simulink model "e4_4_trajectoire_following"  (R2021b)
settings: Solver=FixedStepAuto  StartTime=0.0  StopTime=200  FixedStep=sampleTime  RelTol=1e-3  EnableMultiTasking=on
InitFcn:
  | start;
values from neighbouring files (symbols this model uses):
  k_d_x = 1.65    [start.m]    (also in startSimulation.m = 2)
  k_d_y = 1.52    [start.m]    (also in startSimulation.m = 2.65)
  k_d_yaw = 1    [start.m]    (also in startSimulation.m = 1.6)
  k_d_z = 0.5    [start.m]    (also in startSimulation.m = 1)
  k_i_x = 0.9    [start.m]    (also in startSimulation.m = 0.001)
  k_i_y = 0.91    [start.m]    (also in startSimulation.m = 0.01)
  k_i_yaw = 0.01    [start.m]    (also in startSimulation.m)
  k_i_z = 0.01    [start.m]    (also in startSimulation.m = 0)
  k_p_x = 1.9    [start.m]    (also in startSimulation.m = 1.55)
  k_p_y = 1.9    [start.m]    (also in startSimulation.m = 2.5)
  k_p_yaw = 2    [start.m]    (also in startSimulation.m = 10)
  k_p_z = 2    [start.m]    (also in startSimulation.m = 10)
  sampleTime = 0.01    [start.m]    (also in startSimulation.m)
  saturation_psi = 2    [start.m]    (also in startSimulation.m)
  saturation_x = 2    [start.m]    (also in startSimulation.m)
  saturation_y = 2    [start.m]    (also in startSimulation.m)
  saturation_z = 2    [start.m]    (also in startSimulation.m)
libraries: simulink x2, aerolibanimutils x1

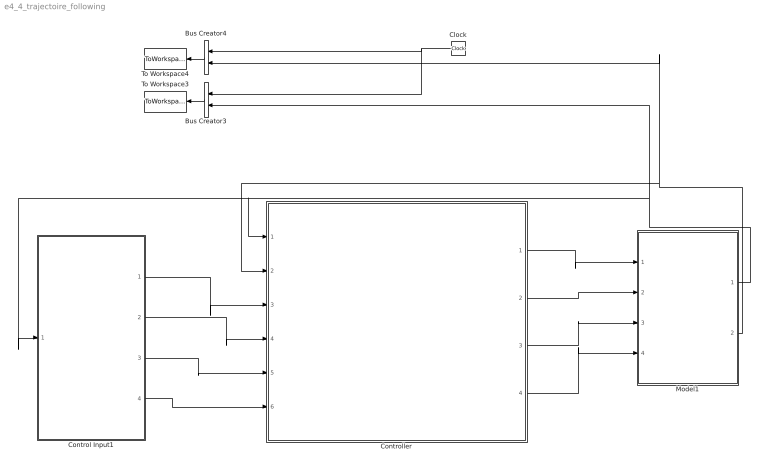
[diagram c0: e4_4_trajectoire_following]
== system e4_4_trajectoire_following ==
  Bus Creator3 : BusCreator  Inputs=2
  Bus Creator4 : BusCreator  Inputs=2
  Clock : Clock
  Control Input1 : Subsystem
  Controller : Subsystem
  Model1 : Subsystem
  To Workspace3 : ToWorkspace  VariableName=r1_pos_array1  SampleTime=-1
  To Workspace4 : ToWorkspace  VariableName=r1_vel_array1  SampleTime=-1
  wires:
  Controller/2(Controller Output Y) -> Model1/2(uy)
  Controller/3(Controller Output H) -> Model1/3(uz)
  Controller/4(Controller Output Psi) -> Model1/4(upsi)
  Model1/2(Output Velocity1) -> Bus Creator4/2, Controller/2(Feedback Velocity)
  Model1/1(Output Postion1) -> Bus Creator3/2, Control Input1/1(Position Feedback), Controller/1(Feedback Position)
  Bus Creator3/1 -> To Workspace3/1
  Clock/1 -> Bus Creator3/1, Bus Creator4/1
  Bus Creator4/1 -> To Workspace4/1
  Control Input1/2(uy) -> Controller/4(Control input Y)
  Control Input1/1(ux) -> Controller/3(Control input X)
  Control Input1/3(uz) -> Controller/5(Control input H)
  Control Input1/4(upsi) -> Controller/6(Control input Psi)
  Controller/1(Controller Output X) -> Model1/1(ux)

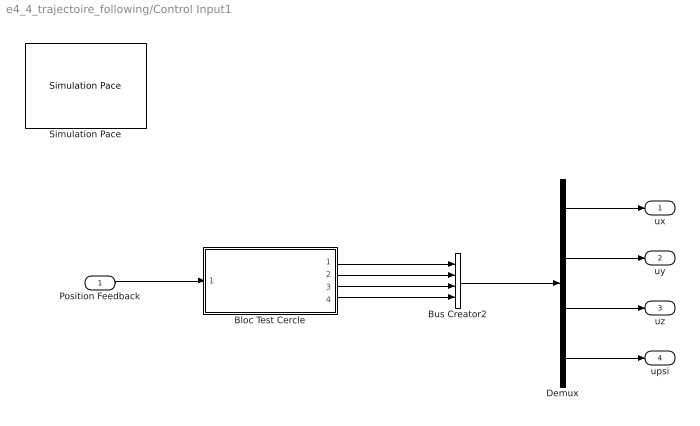
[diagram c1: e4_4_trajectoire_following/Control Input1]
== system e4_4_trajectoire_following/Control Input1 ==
  Position Feedback : Inport
  Bloc Test Cercle : Subsystem
  Bus Creator2 : BusCreator  Inputs=4
  Demux : Demux
  Simulation Pace : aerolibanimutils/Simulation Pace  SimulationPace=100  SleepMode=MATLAB Thread  OutputPaceError=off  SampleTime=-1
  ux : Outport  VectorParamsAs1DForOutWhenUnconnected=off
  uy : Outport  Port=2  VectorParamsAs1DForOutWhenUnconnected=off
  uz : Outport  Port=3  VectorParamsAs1DForOutWhenUnconnected=off
  upsi : Outport  Port=4  VectorParamsAs1DForOutWhenUnconnected=off
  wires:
  Demux/2 -> uy/1
  Demux/1 -> ux/1
  Demux/3 -> uz/1
  Demux/4 -> upsi/1
  Bloc Test Cercle/2(uy) -> Bus Creator2/2
  Bloc Test Cercle/4(upsi) -> Bus Creator2/4
  Position Feedback/1 -> Bloc Test Cercle/1(Position Feedback)
  Bloc Test Cercle/3(uz) -> Bus Creator2/3
  Bus Creator2/1 -> Demux/1
  Bloc Test Cercle/1(ux) -> Bus Creator2/1

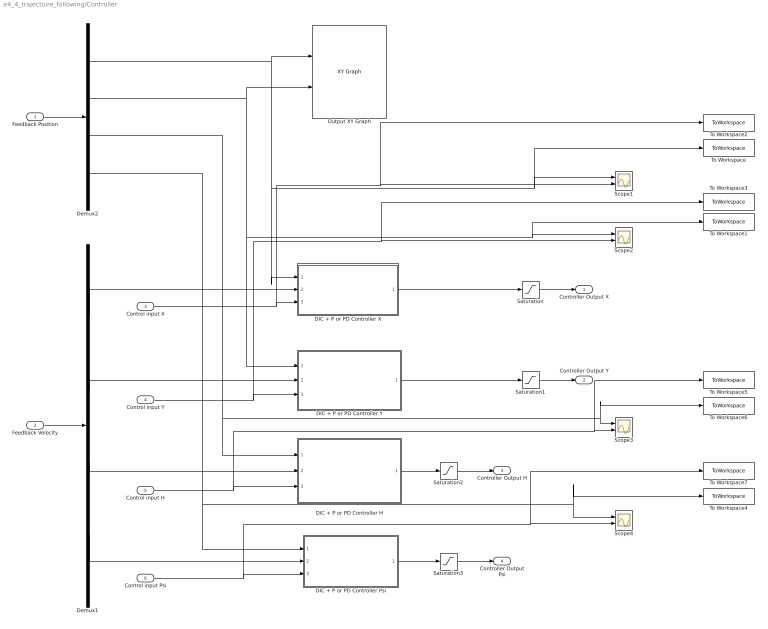
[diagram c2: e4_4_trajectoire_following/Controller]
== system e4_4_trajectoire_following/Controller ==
  Feedback Position : Inport
  Feedback Velocity : Inport  Port=2
  Control input X : Inport  Port=3
  Control input Y : Inport  Port=4
  Control input H : Inport  Port=5
  Control input Psi : Inport  Port=6
  DIC + P or PD Controller H : Subsystem
  DIC + P or PD Controller Psi : Subsystem
  DIC + P or PD Controller X : Subsystem
  DIC + P or PD Controller Y : Subsystem
  Demux1 : Demux
  Demux2 : Demux
  Output XY Graph : simulink/Sinks/XY Graph  xmin=-1  xmax=1  ymin=-1  ymax=1  st=-1
  Saturation : Saturate  UpperLimit=saturation_x  LowerLimit=-saturation_x
  Saturation1 : Saturate  UpperLimit=saturation_y  LowerLimit=-saturation_y
  Saturation2 : Saturate  UpperLimit=saturation_z  LowerLimit=-saturation_z
  Saturation3 : Saturate  UpperLimit=saturation_psi  LowerLimit=-saturation_psi
  Scope{1..4} (4 alike) : Scope  NumInputPorts=2
  To Workspace : ToWorkspace  VariableName=N4_Step1_Out_X  SampleTime=-1
  To Workspace1 : ToWorkspace  VariableName=N4_Step1_Out_Y  SampleTime=-1
  To Workspace2 : ToWorkspace  VariableName=N4_Step1_In_X  SampleTime=-1
  To Workspace3 : ToWorkspace  VariableName=N4_Step1_In_Y  SampleTime=-1
  To Workspace4 : ToWorkspace  VariableName=N4_Step1_Out_Psi  SampleTime=-1
  To Workspace5 : ToWorkspace  VariableName=N4_Step1_In_H  SampleTime=-1
  To Workspace6 : ToWorkspace  VariableName=N4_Step1_Out_H  SampleTime=-1
  To Workspace7 : ToWorkspace  VariableName=N4_Step1_In_Psi  SampleTime=-1
  Controller Output X : Outport  VectorParamsAs1DForOutWhenUnconnected=off
  Controller Output Y : Outport  Port=2  VectorParamsAs1DForOutWhenUnconnected=off
  Controller Output H : Outport  Port=3  VectorParamsAs1DForOutWhenUnconnected=off
  Controller Output Psi : Outport  Port=4  VectorParamsAs1DForOutWhenUnconnected=off
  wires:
  Feedback Position/1 -> Demux2/1
  Feedback Velocity/1 -> Demux1/1
  Demux1/2 -> DIC + P or PD Controller Y/2(Feedback Velocity Y)
  Demux2/3 -> Scope3/1, To Workspace6/1, DIC + P or PD Controller H/1(Feedback Position H)
  Demux1/1 -> DIC + P or PD Controller X/2(Feedback Velocity X)
  Demux1/3 -> DIC + P or PD Controller H/2(Feedback Velocity H)
  Control input X/1 -> To Workspace2/1, Scope1/2, DIC + P or PD Controller X/3(Control Input X)
  Control input H/1 -> Scope3/2, To Workspace5/1, DIC + P or PD Controller H/3(Control Input H)
  Saturation/1 -> Controller Output X/1
  Saturation1/1 -> Controller Output Y/1
  Saturation2/1 -> Controller Output H/1
  Saturation3/1 -> Controller Output Psi/1
  Control input Y/1 -> Scope2/2, To Workspace3/1, DIC + P or PD Controller Y/3(Control Input Y)
  DIC + P or PD Controller H/1(Controller Output H) -> Saturation2/1
  DIC + P or PD Controller Psi/1(Controller Output Psi) -> Saturation3/1
  Demux2/1 -> DIC + P or PD Controller X/1(Feedback Position X), To Workspace/1, Scope1/1, Output XY Graph/1
  Demux2/2 -> Scope2/1, To Workspace1/1, DIC + P or PD Controller Y/1(Feedback Position Y), Output XY Graph/2
  Demux2/4 -> Scope4/1, To Workspace4/1, DIC + P or PD Controller Psi/1(Feedback Position Psi)
  Demux1/4 -> DIC + P or PD Controller Psi/2(Feedback Velocity Psi)
  Control input Psi/1 -> Scope4/2, To Workspace7/1, DIC + P or PD Controller Psi/3(Control input Psi)
  DIC + P or PD Controller Y/1(Controller Output Y) -> Saturation1/1
  DIC + P or PD Controller X/1(Controller Output X) -> Saturation/1

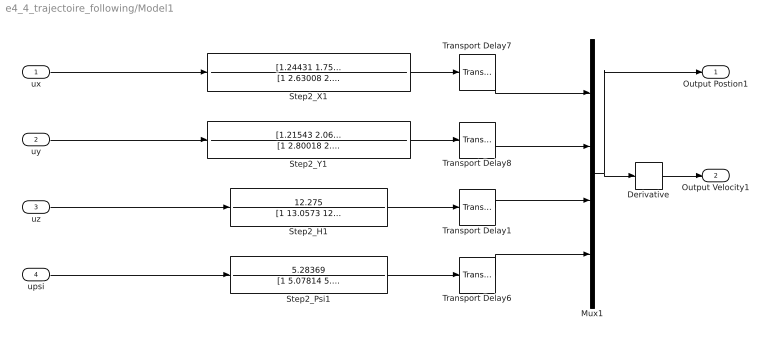
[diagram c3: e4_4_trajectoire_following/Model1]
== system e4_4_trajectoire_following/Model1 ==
  ux : Inport
  uy : Inport  Port=2
  uz : Inport  Port=3
  upsi : Inport  Port=4
  Derivative : Derivative
  Mux1 : Mux
  Step2_H1 : TransferFcn  Numerator=12.275  Denominator=[1 13.0573 12.3932]
  Step2_Psi1 : TransferFcn  Numerator=5.28369  Denominator=[1 5.07814 5.37552]
  Step2_X1 : TransferFcn  Numerator=[1.24431 1.75269]  Denominator=[1 2.63008 2.37405 1.95897]
  Step2_Y1 : TransferFcn  Numerator=[1.21543 2.06629]  Denominator=[1 2.80018 2.54762 2.23605]
  Transport Delay1 : TransportDelay  DelayTime=0.0271
  Transport Delay6 : TransportDelay  DelayTime=0.0281
  Transport Delay7 : TransportDelay  DelayTime=0.3778
  Transport Delay8 : TransportDelay  DelayTime=0.3715
  Output Postion1 : Outport
  Output Velocity1 : Outport  Port=2
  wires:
  upsi/1 -> Step2_Psi1/1
  Transport Delay8/1 -> Mux1/2
  Step2_Y1/1 -> Transport Delay8/1
  Step2_Psi1/1 -> Transport Delay6/1
  Transport Delay6/1 -> Mux1/4
  Transport Delay1/1 -> Mux1/3
  ux/1 -> Step2_X1/1
  Step2_X1/1 -> Transport Delay7/1
  Transport Delay7/1 -> Mux1/1
  Step2_H1/1 -> Transport Delay1/1
  uz/1 -> Step2_H1/1
  uy/1 -> Step2_Y1/1
  Derivative/1 -> Output Velocity1/1
  Mux1/1 -> Derivative/1, Output Postion1/1

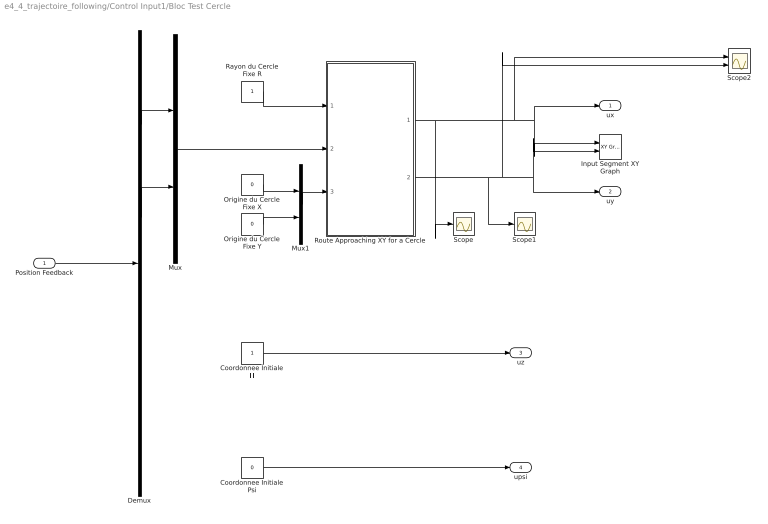
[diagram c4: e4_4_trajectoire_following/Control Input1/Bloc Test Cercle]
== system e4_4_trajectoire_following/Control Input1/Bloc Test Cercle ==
  Position Feedback : Inport
  Coordonnee Initiale H : Constant
  Coordonnee Initiale Psi : Constant  Value=0
  Demux : Demux
  Input Segment XY Graph : simulink/Sinks/XY Graph  xmin=-10  xmax=10  ymin=-10  ymax=10  st=-1
  Mux : Mux  Inputs=2
  Mux1 : Mux  Inputs=2
  Origine du Cercle Fixe X : Constant  Value=0
  Origine du Cercle Fixe Y : Constant  Value=0
  Rayon du Cercle Fixe R : Constant
  Route Approaching XY for a Cercle : MATLAB Function  TreatAsAtomicUnit=on  SystemSampleTime=sampleTime
  Scope : Scope
  Scope1 : Scope
  Scope2 : Scope  NumInputPorts=2
  ux : Outport  VectorParamsAs1DForOutWhenUnconnected=off
  uy : Outport  Port=2  VectorParamsAs1DForOutWhenUnconnected=off
  uz : Outport  Port=3  VectorParamsAs1DForOutWhenUnconnected=off
  upsi : Outport  Port=4  VectorParamsAs1DForOutWhenUnconnected=off
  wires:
  Position Feedback/1 -> Demux/1
  Coordonnee Initiale H/1 -> uz/1
  Coordonnee Initiale Psi/1 -> upsi/1
  Demux/2 -> Mux/2
  Demux/1 -> Mux/1
  Mux/1 -> Route Approaching XY for a Cercle/2(P_feedback)
  Rayon du Cercle Fixe R/1 -> Route Approaching XY for a Cercle/1(P_Rayon)
  Mux1/1 -> Route Approaching XY for a Cercle/3(P_Origine)
  Origine du Cercle Fixe X/1 -> Mux1/1
  Origine du Cercle Fixe Y/1 -> Mux1/2
  Route Approaching XY for a Cercle/2(P_dy) -> Scope2/2, uy/1, Input Segment XY Graph/2, Scope1/1
  Route Approaching XY for a Cercle/1(P_dx) -> Scope2/1, ux/1, Input Segment XY Graph/1, Scope/1

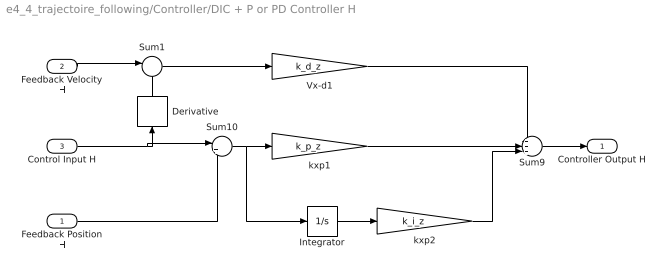
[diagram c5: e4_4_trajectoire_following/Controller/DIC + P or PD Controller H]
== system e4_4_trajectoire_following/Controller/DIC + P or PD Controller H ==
  Feedback Position H : Inport
  Feedback Velocity H : Inport  Port=2
  Control Input H : Inport  Port=3
  Derivative : Derivative
  Integrator : Integrator
  Sum1 : Sum  Inputs=|-+
  Sum10 : Sum  Inputs=|+-
  Sum9 : Sum  Inputs=+++|
  Vx-d1 : Gain  Gain=k_d_z
  kxp1 : Gain  Gain=k_p_z
  kxp2 : Gain  Gain=k_i_z
  Controller Output H : Outport  VectorParamsAs1DForOutWhenUnconnected=off
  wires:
  Sum9/1 -> Controller Output H/1
  Sum10/1 -> Integrator/1, kxp1/1
  kxp1/1 -> Sum9/2
  Vx-d1/1 -> Sum9/1
  Feedback Velocity H/1 -> Sum1/1
  Sum1/1 -> Vx-d1/1
  Integrator/1 -> kxp2/1
  kxp2/1 -> Sum9/3
  Control Input H/1 -> Sum10/1, Derivative/1
  Feedback Position H/1 -> Sum10/2
  Derivative/1 -> Sum1/2

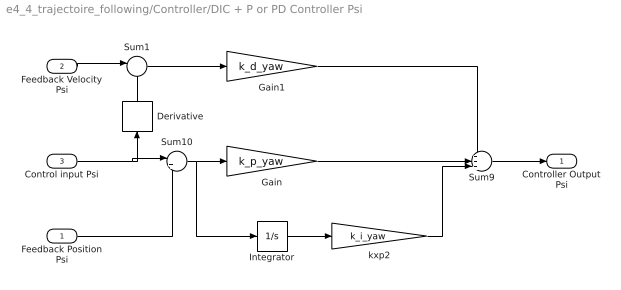
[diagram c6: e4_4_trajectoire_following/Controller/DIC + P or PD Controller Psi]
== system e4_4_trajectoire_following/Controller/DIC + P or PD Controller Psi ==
  Feedback Position Psi : Inport
  Feedback Velocity Psi : Inport  Port=2
  Control input Psi : Inport  Port=3
  Derivative : Derivative
  Gain : Gain  Gain=k_p_yaw
  Gain1 : Gain  Gain=k_d_yaw
  Integrator : Integrator
  Sum1 : Sum  Inputs=|-+
  Sum10 : Sum  Inputs=|+-
  Sum9 : Sum  Inputs=+++|
  kxp2 : Gain  Gain=k_i_yaw
  Controller Output Psi : Outport  VectorParamsAs1DForOutWhenUnconnected=off
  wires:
  Sum9/1 -> Controller Output Psi/1
  kxp2/1 -> Sum9/3
  Control input Psi/1 -> Sum10/1, Derivative/1
  Gain1/1 -> Sum9/1
  Sum10/1 -> Gain/1, Integrator/1
  Integrator/1 -> kxp2/1
  Feedback Velocity Psi/1 -> Sum1/1
  Sum1/1 -> Gain1/1
  Gain/1 -> Sum9/2
  Derivative/1 -> Sum1/2
  Feedback Position Psi/1 -> Sum10/2

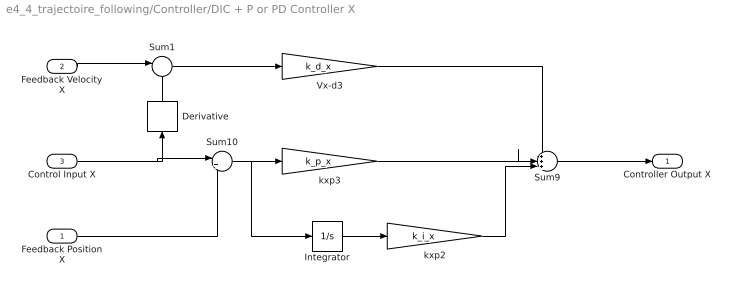
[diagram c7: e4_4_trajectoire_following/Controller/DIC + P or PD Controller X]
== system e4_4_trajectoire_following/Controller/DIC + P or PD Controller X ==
  Feedback Position X : Inport
  Feedback Velocity X : Inport  Port=2
  Control Input X : Inport  Port=3
  Derivative : Derivative
  Integrator : Integrator
  Sum1 : Sum  Inputs=|-+
  Sum10 : Sum  Inputs=|+-
  Sum9 : Sum  Inputs=+++|
  Vx-d3 : Gain  Gain=k_d_x
  kxp2 : Gain  Gain=k_i_x
  kxp3 : Gain  Gain=k_p_x
  Controller Output X : Outport  VectorParamsAs1DForOutWhenUnconnected=off
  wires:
  Sum9/1 -> Controller Output X/1
  Feedback Velocity X/1 -> Sum1/1
  Feedback Position X/1 -> Sum10/2
  Sum1/1 -> Vx-d3/1
  Integrator/1 -> kxp2/1
  kxp3/1 -> Sum9/2
  Vx-d3/1 -> Sum9/1
  Sum10/1 -> kxp3/1, Integrator/1
  Derivative/1 -> Sum1/2
  kxp2/1 -> Sum9/3
  Control Input X/1 -> Sum10/1, Derivative/1

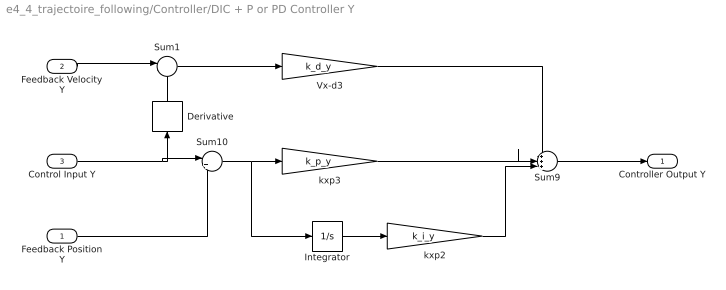
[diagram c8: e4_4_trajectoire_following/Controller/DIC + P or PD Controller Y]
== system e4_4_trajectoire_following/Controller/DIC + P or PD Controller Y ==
  Feedback Position Y : Inport
  Feedback Velocity Y : Inport  Port=2
  Control Input Y : Inport  Port=3
  Derivative : Derivative
  Integrator : Integrator
  Sum1 : Sum  Inputs=|-+
  Sum10 : Sum  Inputs=|+-
  Sum9 : Sum  Inputs=+++|
  Vx-d3 : Gain  Gain=k_d_y
  kxp2 : Gain  Gain=k_i_y
  kxp3 : Gain  Gain=k_p_y
  Controller Output Y : Outport  VectorParamsAs1DForOutWhenUnconnected=off
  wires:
  Feedback Position Y/1 -> Sum10/2
  Control Input Y/1 -> Sum10/1, Derivative/1
  Sum9/1 -> Controller Output Y/1
  Integrator/1 -> kxp2/1
  kxp3/1 -> Sum9/2
  Sum10/1 -> kxp3/1, Integrator/1
  kxp2/1 -> Sum9/3
  Vx-d3/1 -> Sum9/1
  Feedback Velocity Y/1 -> Sum1/1
  Sum1/1 -> Vx-d3/1
  Derivative/1 -> Sum1/2

== matlab function e4_4_trajectoire_following/Control Input1/Bloc Test 
Cercle/Route Approaching XY for a Cercle ==
function [P_dx,P_dy] = fcn(P_Rayon, P_feedback, P_Origine)

% determine the constants
a0  = 3;

% the parameters of PD controller: 1/k2
% according to P287 of 《多旋翼飞行器设计与控制》,
% these two parameters should be equal? Is that true?

% global k2_p_x;
% global k2_d_x;
% k2_p_x=0.1;
% k2_d_x=0.1;

% the parameter of 'approaching'
% k0_x=0.3;
% k1_x=0.3;
% k0_x=0.3;
% k1_x=0.7;
k0_x=0.3;
k1_x=1;

P_init=[0;0]; % the initialized position of UAV
persistent P_static;
if isempty(P_static)
 P_static=P_init; % the initilized value of position for giving a initial UAV position
 end
 P_static = P_feedback; % Except the initialization, the following position is gotten by the feedback 
 P_perp_rayon = P_Origine+(P_static-P_Origine)*(P_Rayon/(norm((P_static-P_Origine)+ 0.000001)));
 A = P_Rayon*[0,1;-1,0]*(((P_perp_rayon - P_Origine)+0.000001)/(norm((P_perp_rayon - P_Origine))+0.000001));
 temp  = satgd(k0_x*A+k1_x*(P_perp_rayon-P_static),a0);
 P_d0 = P_static + temp;
P_dx=P_d0(1);
P_dy=P_d0(2);
